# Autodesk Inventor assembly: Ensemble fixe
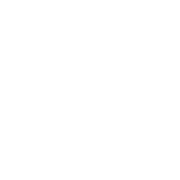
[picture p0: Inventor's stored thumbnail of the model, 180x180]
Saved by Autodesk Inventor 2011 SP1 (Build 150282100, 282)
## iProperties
Created: 2010-12
Part Number: Ensemble fixe
Document SubType Name: Assembly
Designer: eric
Author: eric
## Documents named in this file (30)
- D:\eduinventor\maquettesaip2011\machineàpain\Workspace\Ensemble fixe.iam
- D:\eduinventor\maquettesaip2011\machineàpain\Workspace\Ensemble carter.iam
- D:\eduinventor\maquettesaip2011\machineàpain\Workspace\enceinte de cuisson.ipt
- D:\eduinventor\maquettesaip2011\machineàpain\Workspace\socle.ipt
- D:\eduinventor\maquettesaip2011\machineàpain\Workspace\Ensemble carte electronique.iam
- D:\eduinventor\maquettesaip2011\machineàpain\Workspace\embase de moule de cuisson.ipt
- D:\eduinventor\maquettesaip2011\machineàpain\Workspace\Ensemble moteur.iam
- D:\eduinventor\maquettesaip2011\machineàpain\Workspace\Ensemble moule de cuisson.iam
- D:\eduinventor\maquettesaip2011\machineàpain\Workspace\Ensemble visserie pour moteur.iam
- D:\eduinventor\maquettesaip2011\machineàpain\Workspace\ressort de maintient du moule.ipt
- D:\eduinventor\maquettesaip2011\machineàpain\Workspace\joint.ipt
- D:\eduinventor\maquettesaip2011\machineàpain\Workspace\ressort de joint.ipt
- D:\eduinventor\maquettesaip2011\machineàpain\Workspace\Symétrieressort de joint.ipt
- D:\eduinventor\maquettesaip2011\machineàpain\Workspace\Symétriejoint.ipt
- D:\eduinventor\maquettesaip2011\machineàpain\Workspace\colerette.ipt
- D:\eduinventor\maquettesaip2011\machineàpain\Workspace\Symétriecolerette.ipt
- D:\eduinventor\maquettesaip2011\machineàpain\Workspace\rivet.ipt
- D:\eduinventor\maquettesaip2011\machineàpain\Workspace\rivet2.ipt
- D:\eduinventor\maquettesaip2011\machineàpain\Workspace\courroie motrice.ipt
- D:\eduinventor\maquettesaip2011\machineàpain\Workspace\courroie intermediaire.ipt
- D:\eduinventor\maquettesaip2011\machineàpain\Workspace\vis M4x6.ipt
- D:\eduinventor\maquettesaip2011\machineàpain\Workspace\vis M4x7.ipt
- D:\eduinventor\maquettesaip2011\machineàpain\Workspace\support de poulie.ipt
- D:\eduinventor\maquettesaip2011\machineàpain\Workspace\patin de cuve.ipt
- D:\eduinventor\maquettesaip2011\machineàpain\Workspace\coussinet 10 16x16.ipt
- D:\eduinventor\maquettesaip2011\machineàpain\Workspace\condensateur.ipt
- D:\eduinventor\maquettesaip2011\machineàpain\Workspace\Ensemble chauffant.iam
- D:\eduinventor\maquettesaip2011\machineàpain\Workspace\resitance chauffante.ipt
- D:\eduinventor\maquettesaip2011\machineàpain\Workspace\attache de resistante chauffante.ipt
- D:\eduinventor\maquettesaip2011\machineàpain\Workspace\patte de fixation.ipt
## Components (54 placed, 29 different names)
1. resitance chauffante:1
2. Ensemble chauffant:1 [sub-assembly]
3. attache de resistante chauffante:1
4. patte de fixation:1
5. patin de cuve:1
6. patin de cuve:4
7. patin de cuve:5
8. patin de cuve:6
9. coussinet 10 16x16:1
10. coussinet 10 16x16:2
11. support de poulie:1
12. vis M4x7:1
13. vis M4x7:2
14. vis M4x6:4
15. vis M4x6:5
16. vis M4x6:6
17. vis M4x6:7
18. vis M4x6:8
19. vis M4x6:9
20. vis M4x6:10
21. vis M4x6:11
22. vis M4x6:12
23. vis M4x6:16
24. vis M4x6:18
25. vis M4x6:19
26. vis M4x6:20
27. vis M4x6:21
28. vis M4x6:22
29. vis M4x6:23
30. courroie intermediaire:1
31. Ensemble visserie pour moteur:4 [sub-assembly]
32. Ensemble visserie pour moteur:3 [sub-assembly]
33. courroie motrice:1
34. joint:1
35. ressort de joint:1
36. Symétrieressort de joint:1
37. Symétriejoint:1
38. colerette:1
39. Symétriecolerette:1
40. rivet:1
41. rivet:2
42. rivet2:1
43. rivet2:2
44. ressort de maintient du moule:1
45. ressort de maintient du moule:2
46. Ensemble visserie pour moteur:1 [sub-assembly]
47. Ensemble moteur:1 [sub-assembly]
48. condensateur:1
49. Ensemble carte electronique:1 [sub-assembly]
50. socle:1
51. embase de moule de cuisson:1
52. enceinte de cuisson:1
53. Ensemble moule de cuisson:1 [sub-assembly]
54. Ensemble carter:1 [sub-assembly]
